VERSION 5.8 ;
BUSBITCHARS "[]" ;
DIVIDERCHAR "/" ;
UNITS
    DATABASE MICRONS 2000 ;
END UNITS

VIA uart_tx_via1_2_960_340_1_3_300_300
  VIARULE Via1Array-0 ;
  CUTSIZE 0.07 0.07 ;
  LAYERS metal1 via1 metal2 ;
  CUTSPACING 0.08 0.08 ;
  ENCLOSURE 0.035 0.05 0.035 0.035 ;
  ROWCOL 1 3 ;
END uart_tx_via1_2_960_340_1_3_300_300

VIA uart_tx_via2_3_960_340_1_3_320_320
  VIARULE Via2Array-0 ;
  CUTSIZE 0.07 0.07 ;
  LAYERS metal2 via2 metal3 ;
  CUTSPACING 0.09 0.09 ;
  ENCLOSURE 0.035 0.035 0.035 0.035 ;
  ROWCOL 1 3 ;
END uart_tx_via2_3_960_340_1_3_320_320

VIA uart_tx_via3_4_960_340_1_3_320_320
  VIARULE Via3Array-0 ;
  CUTSIZE 0.07 0.07 ;
  LAYERS metal3 via3 metal4 ;
  CUTSPACING 0.09 0.09 ;
  ENCLOSURE 0.035 0.035 0.045 0.035 ;
  ROWCOL 1 3 ;
END uart_tx_via3_4_960_340_1_3_320_320

VIA uart_tx_via4_5_960_2800_5_2_600_600
  VIARULE Via4Array-0 ;
  CUTSIZE 0.14 0.14 ;
  LAYERS metal4 via4 metal5 ;
  CUTSPACING 0.16 0.16 ;
  ENCLOSURE 0.02 0 0 0 ;
  ROWCOL 5 2 ;
END uart_tx_via4_5_960_2800_5_2_600_600

VIA uart_tx_via5_6_960_2800_5_2_600_600
  VIARULE Via5Array-0 ;
  CUTSIZE 0.14 0.14 ;
  LAYERS metal5 via5 metal6 ;
  CUTSPACING 0.16 0.16 ;
  ENCLOSURE 0 0 0 0 ;
  ROWCOL 5 2 ;
END uart_tx_via5_6_960_2800_5_2_600_600

VIA uart_tx_via6_7_960_2800_4_1_600_600
  VIARULE Via6Array-0 ;
  CUTSIZE 0.14 0.14 ;
  LAYERS metal6 via6 metal7 ;
  CUTSPACING 0.16 0.16 ;
  ENCLOSURE 0 0 0.13 0.18 ;
  ROWCOL 4 1 ;
END uart_tx_via6_7_960_2800_4_1_600_600

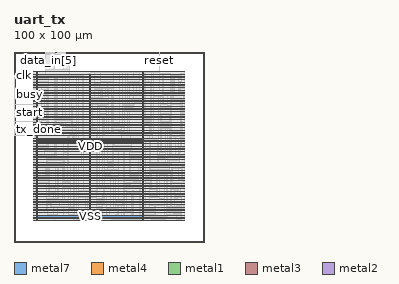
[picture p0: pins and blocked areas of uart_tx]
MACRO uart_tx
  FOREIGN uart_tx 0 0 ;
  CLASS BLOCK ;
  SIZE 100 BY 100 ;
  PIN VSS
    USE GROUND ;
    DIRECTION INOUT ;
    PORT
      LAYER metal7 ;
        RECT  11.83 52.5 68.31 53.9 ;
        RECT  11.83 12.5 68.31 13.9 ;
      LAYER metal4 ;
        RECT  67.83 11.115 68.31 89.685 ;
        RECT  11.83 11.115 12.31 89.685 ;
      LAYER metal1 ;
        RECT  10.07 89.515 89.87 89.685 ;
        RECT  10.07 86.715 89.87 86.885 ;
        RECT  10.07 83.915 89.87 84.085 ;
        RECT  10.07 81.115 89.87 81.285 ;
        RECT  10.07 78.315 89.87 78.485 ;
        RECT  10.07 75.515 89.87 75.685 ;
        RECT  10.07 72.715 89.87 72.885 ;
        RECT  10.07 69.915 89.87 70.085 ;
        RECT  10.07 67.115 89.87 67.285 ;
        RECT  10.07 64.315 89.87 64.485 ;
        RECT  10.07 61.515 89.87 61.685 ;
        RECT  10.07 58.715 89.87 58.885 ;
        RECT  10.07 55.915 89.87 56.085 ;
        RECT  10.07 53.115 89.87 53.285 ;
        RECT  10.07 50.315 89.87 50.485 ;
        RECT  10.07 47.515 89.87 47.685 ;
        RECT  10.07 44.715 89.87 44.885 ;
        RECT  10.07 41.915 89.87 42.085 ;
        RECT  10.07 39.115 89.87 39.285 ;
        RECT  10.07 36.315 89.87 36.485 ;
        RECT  10.07 33.515 89.87 33.685 ;
        RECT  10.07 30.715 89.87 30.885 ;
        RECT  10.07 27.915 89.87 28.085 ;
        RECT  10.07 25.115 89.87 25.285 ;
        RECT  10.07 22.315 89.87 22.485 ;
        RECT  10.07 19.515 89.87 19.685 ;
        RECT  10.07 16.715 89.87 16.885 ;
        RECT  10.07 13.915 89.87 14.085 ;
        RECT  10.07 11.115 89.87 11.285 ;
      VIA 68.07 53.2 uart_tx_via6_7_960_2800_4_1_600_600 ;
      VIA 68.07 53.2 uart_tx_via5_6_960_2800_5_2_600_600 ;
      VIA 68.07 53.2 uart_tx_via4_5_960_2800_5_2_600_600 ;
      VIA 68.07 13.2 uart_tx_via6_7_960_2800_4_1_600_600 ;
      VIA 68.07 13.2 uart_tx_via5_6_960_2800_5_2_600_600 ;
      VIA 68.07 13.2 uart_tx_via4_5_960_2800_5_2_600_600 ;
      VIA 12.07 53.2 uart_tx_via6_7_960_2800_4_1_600_600 ;
      VIA 12.07 53.2 uart_tx_via5_6_960_2800_5_2_600_600 ;
      VIA 12.07 53.2 uart_tx_via4_5_960_2800_5_2_600_600 ;
      VIA 12.07 13.2 uart_tx_via6_7_960_2800_4_1_600_600 ;
      VIA 12.07 13.2 uart_tx_via5_6_960_2800_5_2_600_600 ;
      VIA 12.07 13.2 uart_tx_via4_5_960_2800_5_2_600_600 ;
      VIA 68.07 89.6 uart_tx_via3_4_960_340_1_3_320_320 ;
      VIA 68.07 89.6 uart_tx_via2_3_960_340_1_3_320_320 ;
      VIA 68.07 89.6 uart_tx_via1_2_960_340_1_3_300_300 ;
      VIA 68.07 86.8 uart_tx_via3_4_960_340_1_3_320_320 ;
      VIA 68.07 86.8 uart_tx_via2_3_960_340_1_3_320_320 ;
      VIA 68.07 86.8 uart_tx_via1_2_960_340_1_3_300_300 ;
      VIA 68.07 84 uart_tx_via3_4_960_340_1_3_320_320 ;
      VIA 68.07 84 uart_tx_via2_3_960_340_1_3_320_320 ;
      VIA 68.07 84 uart_tx_via1_2_960_340_1_3_300_300 ;
      VIA 68.07 81.2 uart_tx_via3_4_960_340_1_3_320_320 ;
      VIA 68.07 81.2 uart_tx_via2_3_960_340_1_3_320_320 ;
      VIA 68.07 81.2 uart_tx_via1_2_960_340_1_3_300_300 ;
      VIA 68.07 78.4 uart_tx_via3_4_960_340_1_3_320_320 ;
      VIA 68.07 78.4 uart_tx_via2_3_960_340_1_3_320_320 ;
      VIA 68.07 78.4 uart_tx_via1_2_960_340_1_3_300_300 ;
      VIA 68.07 75.6 uart_tx_via3_4_960_340_1_3_320_320 ;
      VIA 68.07 75.6 uart_tx_via2_3_960_340_1_3_320_320 ;
      VIA 68.07 75.6 uart_tx_via1_2_960_340_1_3_300_300 ;
      VIA 68.07 72.8 uart_tx_via3_4_960_340_1_3_320_320 ;
      VIA 68.07 72.8 uart_tx_via2_3_960_340_1_3_320_320 ;
      VIA 68.07 72.8 uart_tx_via1_2_960_340_1_3_300_300 ;
      VIA 68.07 70 uart_tx_via3_4_960_340_1_3_320_320 ;
      VIA 68.07 70 uart_tx_via2_3_960_340_1_3_320_320 ;
      VIA 68.07 70 uart_tx_via1_2_960_340_1_3_300_300 ;
      VIA 68.07 67.2 uart_tx_via3_4_960_340_1_3_320_320 ;
      VIA 68.07 67.2 uart_tx_via2_3_960_340_1_3_320_320 ;
      VIA 68.07 67.2 uart_tx_via1_2_960_340_1_3_300_300 ;
      VIA 68.07 64.4 uart_tx_via3_4_960_340_1_3_320_320 ;
      VIA 68.07 64.4 uart_tx_via2_3_960_340_1_3_320_320 ;
      VIA 68.07 64.4 uart_tx_via1_2_960_340_1_3_300_300 ;
      VIA 68.07 61.6 uart_tx_via3_4_960_340_1_3_320_320 ;
      VIA 68.07 61.6 uart_tx_via2_3_960_340_1_3_320_320 ;
      VIA 68.07 61.6 uart_tx_via1_2_960_340_1_3_300_300 ;
      VIA 68.07 58.8 uart_tx_via3_4_960_340_1_3_320_320 ;
      VIA 68.07 58.8 uart_tx_via2_3_960_340_1_3_320_320 ;
      VIA 68.07 58.8 uart_tx_via1_2_960_340_1_3_300_300 ;
      VIA 68.07 56 uart_tx_via3_4_960_340_1_3_320_320 ;
      VIA 68.07 56 uart_tx_via2_3_960_340_1_3_320_320 ;
      VIA 68.07 56 uart_tx_via1_2_960_340_1_3_300_300 ;
      VIA 68.07 53.2 uart_tx_via3_4_960_340_1_3_320_320 ;
      VIA 68.07 53.2 uart_tx_via2_3_960_340_1_3_320_320 ;
      VIA 68.07 53.2 uart_tx_via1_2_960_340_1_3_300_300 ;
      VIA 68.07 50.4 uart_tx_via3_4_960_340_1_3_320_320 ;
      VIA 68.07 50.4 uart_tx_via2_3_960_340_1_3_320_320 ;
      VIA 68.07 50.4 uart_tx_via1_2_960_340_1_3_300_300 ;
      VIA 68.07 47.6 uart_tx_via3_4_960_340_1_3_320_320 ;
      VIA 68.07 47.6 uart_tx_via2_3_960_340_1_3_320_320 ;
      VIA 68.07 47.6 uart_tx_via1_2_960_340_1_3_300_300 ;
      VIA 68.07 44.8 uart_tx_via3_4_960_340_1_3_320_320 ;
      VIA 68.07 44.8 uart_tx_via2_3_960_340_1_3_320_320 ;
      VIA 68.07 44.8 uart_tx_via1_2_960_340_1_3_300_300 ;
      VIA 68.07 42 uart_tx_via3_4_960_340_1_3_320_320 ;
      VIA 68.07 42 uart_tx_via2_3_960_340_1_3_320_320 ;
      VIA 68.07 42 uart_tx_via1_2_960_340_1_3_300_300 ;
      VIA 68.07 39.2 uart_tx_via3_4_960_340_1_3_320_320 ;
      VIA 68.07 39.2 uart_tx_via2_3_960_340_1_3_320_320 ;
      VIA 68.07 39.2 uart_tx_via1_2_960_340_1_3_300_300 ;
      VIA 68.07 36.4 uart_tx_via3_4_960_340_1_3_320_320 ;
      VIA 68.07 36.4 uart_tx_via2_3_960_340_1_3_320_320 ;
      VIA 68.07 36.4 uart_tx_via1_2_960_340_1_3_300_300 ;
      VIA 68.07 33.6 uart_tx_via3_4_960_340_1_3_320_320 ;
      VIA 68.07 33.6 uart_tx_via2_3_960_340_1_3_320_320 ;
      VIA 68.07 33.6 uart_tx_via1_2_960_340_1_3_300_300 ;
      VIA 68.07 30.8 uart_tx_via3_4_960_340_1_3_320_320 ;
      VIA 68.07 30.8 uart_tx_via2_3_960_340_1_3_320_320 ;
      VIA 68.07 30.8 uart_tx_via1_2_960_340_1_3_300_300 ;
      VIA 68.07 28 uart_tx_via3_4_960_340_1_3_320_320 ;
      VIA 68.07 28 uart_tx_via2_3_960_340_1_3_320_320 ;
      VIA 68.07 28 uart_tx_via1_2_960_340_1_3_300_300 ;
      VIA 68.07 25.2 uart_tx_via3_4_960_340_1_3_320_320 ;
      VIA 68.07 25.2 uart_tx_via2_3_960_340_1_3_320_320 ;
      VIA 68.07 25.2 uart_tx_via1_2_960_340_1_3_300_300 ;
      VIA 68.07 22.4 uart_tx_via3_4_960_340_1_3_320_320 ;
      VIA 68.07 22.4 uart_tx_via2_3_960_340_1_3_320_320 ;
      VIA 68.07 22.4 uart_tx_via1_2_960_340_1_3_300_300 ;
      VIA 68.07 19.6 uart_tx_via3_4_960_340_1_3_320_320 ;
      VIA 68.07 19.6 uart_tx_via2_3_960_340_1_3_320_320 ;
      VIA 68.07 19.6 uart_tx_via1_2_960_340_1_3_300_300 ;
      VIA 68.07 16.8 uart_tx_via3_4_960_340_1_3_320_320 ;
      VIA 68.07 16.8 uart_tx_via2_3_960_340_1_3_320_320 ;
      VIA 68.07 16.8 uart_tx_via1_2_960_340_1_3_300_300 ;
      VIA 68.07 14 uart_tx_via3_4_960_340_1_3_320_320 ;
      VIA 68.07 14 uart_tx_via2_3_960_340_1_3_320_320 ;
      VIA 68.07 14 uart_tx_via1_2_960_340_1_3_300_300 ;
      VIA 68.07 11.2 uart_tx_via3_4_960_340_1_3_320_320 ;
      VIA 68.07 11.2 uart_tx_via2_3_960_340_1_3_320_320 ;
      VIA 68.07 11.2 uart_tx_via1_2_960_340_1_3_300_300 ;
      VIA 12.07 89.6 uart_tx_via3_4_960_340_1_3_320_320 ;
      VIA 12.07 89.6 uart_tx_via2_3_960_340_1_3_320_320 ;
      VIA 12.07 89.6 uart_tx_via1_2_960_340_1_3_300_300 ;
      VIA 12.07 86.8 uart_tx_via3_4_960_340_1_3_320_320 ;
      VIA 12.07 86.8 uart_tx_via2_3_960_340_1_3_320_320 ;
      VIA 12.07 86.8 uart_tx_via1_2_960_340_1_3_300_300 ;
      VIA 12.07 84 uart_tx_via3_4_960_340_1_3_320_320 ;
      VIA 12.07 84 uart_tx_via2_3_960_340_1_3_320_320 ;
      VIA 12.07 84 uart_tx_via1_2_960_340_1_3_300_300 ;
      VIA 12.07 81.2 uart_tx_via3_4_960_340_1_3_320_320 ;
      VIA 12.07 81.2 uart_tx_via2_3_960_340_1_3_320_320 ;
      VIA 12.07 81.2 uart_tx_via1_2_960_340_1_3_300_300 ;
      VIA 12.07 78.4 uart_tx_via3_4_960_340_1_3_320_320 ;
      VIA 12.07 78.4 uart_tx_via2_3_960_340_1_3_320_320 ;
      VIA 12.07 78.4 uart_tx_via1_2_960_340_1_3_300_300 ;
      VIA 12.07 75.6 uart_tx_via3_4_960_340_1_3_320_320 ;
      VIA 12.07 75.6 uart_tx_via2_3_960_340_1_3_320_320 ;
      VIA 12.07 75.6 uart_tx_via1_2_960_340_1_3_300_300 ;
      VIA 12.07 72.8 uart_tx_via3_4_960_340_1_3_320_320 ;
      VIA 12.07 72.8 uart_tx_via2_3_960_340_1_3_320_320 ;
      VIA 12.07 72.8 uart_tx_via1_2_960_340_1_3_300_300 ;
      VIA 12.07 70 uart_tx_via3_4_960_340_1_3_320_320 ;
      VIA 12.07 70 uart_tx_via2_3_960_340_1_3_320_320 ;
      VIA 12.07 70 uart_tx_via1_2_960_340_1_3_300_300 ;
      VIA 12.07 67.2 uart_tx_via3_4_960_340_1_3_320_320 ;
      VIA 12.07 67.2 uart_tx_via2_3_960_340_1_3_320_320 ;
      VIA 12.07 67.2 uart_tx_via1_2_960_340_1_3_300_300 ;
      VIA 12.07 64.4 uart_tx_via3_4_960_340_1_3_320_320 ;
      VIA 12.07 64.4 uart_tx_via2_3_960_340_1_3_320_320 ;
      VIA 12.07 64.4 uart_tx_via1_2_960_340_1_3_300_300 ;
      VIA 12.07 61.6 uart_tx_via3_4_960_340_1_3_320_320 ;
      VIA 12.07 61.6 uart_tx_via2_3_960_340_1_3_320_320 ;
      VIA 12.07 61.6 uart_tx_via1_2_960_340_1_3_300_300 ;
      VIA 12.07 58.8 uart_tx_via3_4_960_340_1_3_320_320 ;
      VIA 12.07 58.8 uart_tx_via2_3_960_340_1_3_320_320 ;
      VIA 12.07 58.8 uart_tx_via1_2_960_340_1_3_300_300 ;
      VIA 12.07 56 uart_tx_via3_4_960_340_1_3_320_320 ;
      VIA 12.07 56 uart_tx_via2_3_960_340_1_3_320_320 ;
      VIA 12.07 56 uart_tx_via1_2_960_340_1_3_300_300 ;
      VIA 12.07 53.2 uart_tx_via3_4_960_340_1_3_320_320 ;
      VIA 12.07 53.2 uart_tx_via2_3_960_340_1_3_320_320 ;
      VIA 12.07 53.2 uart_tx_via1_2_960_340_1_3_300_300 ;
      VIA 12.07 50.4 uart_tx_via3_4_960_340_1_3_320_320 ;
      VIA 12.07 50.4 uart_tx_via2_3_960_340_1_3_320_320 ;
      VIA 12.07 50.4 uart_tx_via1_2_960_340_1_3_300_300 ;
      VIA 12.07 47.6 uart_tx_via3_4_960_340_1_3_320_320 ;
      VIA 12.07 47.6 uart_tx_via2_3_960_340_1_3_320_320 ;
      VIA 12.07 47.6 uart_tx_via1_2_960_340_1_3_300_300 ;
      VIA 12.07 44.8 uart_tx_via3_4_960_340_1_3_320_320 ;
      VIA 12.07 44.8 uart_tx_via2_3_960_340_1_3_320_320 ;
      VIA 12.07 44.8 uart_tx_via1_2_960_340_1_3_300_300 ;
      VIA 12.07 42 uart_tx_via3_4_960_340_1_3_320_320 ;
      VIA 12.07 42 uart_tx_via2_3_960_340_1_3_320_320 ;
      VIA 12.07 42 uart_tx_via1_2_960_340_1_3_300_300 ;
      VIA 12.07 39.2 uart_tx_via3_4_960_340_1_3_320_320 ;
      VIA 12.07 39.2 uart_tx_via2_3_960_340_1_3_320_320 ;
      VIA 12.07 39.2 uart_tx_via1_2_960_340_1_3_300_300 ;
      VIA 12.07 36.4 uart_tx_via3_4_960_340_1_3_320_320 ;
      VIA 12.07 36.4 uart_tx_via2_3_960_340_1_3_320_320 ;
      VIA 12.07 36.4 uart_tx_via1_2_960_340_1_3_300_300 ;
      VIA 12.07 33.6 uart_tx_via3_4_960_340_1_3_320_320 ;
      VIA 12.07 33.6 uart_tx_via2_3_960_340_1_3_320_320 ;
      VIA 12.07 33.6 uart_tx_via1_2_960_340_1_3_300_300 ;
      VIA 12.07 30.8 uart_tx_via3_4_960_340_1_3_320_320 ;
      VIA 12.07 30.8 uart_tx_via2_3_960_340_1_3_320_320 ;
      VIA 12.07 30.8 uart_tx_via1_2_960_340_1_3_300_300 ;
      VIA 12.07 28 uart_tx_via3_4_960_340_1_3_320_320 ;
      VIA 12.07 28 uart_tx_via2_3_960_340_1_3_320_320 ;
      VIA 12.07 28 uart_tx_via1_2_960_340_1_3_300_300 ;
      VIA 12.07 25.2 uart_tx_via3_4_960_340_1_3_320_320 ;
      VIA 12.07 25.2 uart_tx_via2_3_960_340_1_3_320_320 ;
      VIA 12.07 25.2 uart_tx_via1_2_960_340_1_3_300_300 ;
      VIA 12.07 22.4 uart_tx_via3_4_960_340_1_3_320_320 ;
      VIA 12.07 22.4 uart_tx_via2_3_960_340_1_3_320_320 ;
      VIA 12.07 22.4 uart_tx_via1_2_960_340_1_3_300_300 ;
      VIA 12.07 19.6 uart_tx_via3_4_960_340_1_3_320_320 ;
      VIA 12.07 19.6 uart_tx_via2_3_960_340_1_3_320_320 ;
      VIA 12.07 19.6 uart_tx_via1_2_960_340_1_3_300_300 ;
      VIA 12.07 16.8 uart_tx_via3_4_960_340_1_3_320_320 ;
      VIA 12.07 16.8 uart_tx_via2_3_960_340_1_3_320_320 ;
      VIA 12.07 16.8 uart_tx_via1_2_960_340_1_3_300_300 ;
      VIA 12.07 14 uart_tx_via3_4_960_340_1_3_320_320 ;
      VIA 12.07 14 uart_tx_via2_3_960_340_1_3_320_320 ;
      VIA 12.07 14 uart_tx_via1_2_960_340_1_3_300_300 ;
      VIA 12.07 11.2 uart_tx_via3_4_960_340_1_3_320_320 ;
      VIA 12.07 11.2 uart_tx_via2_3_960_340_1_3_320_320 ;
      VIA 12.07 11.2 uart_tx_via1_2_960_340_1_3_300_300 ;
    END
  END VSS
  PIN VDD
    USE POWER ;
    DIRECTION INOUT ;
    PORT
      LAYER metal4 ;
        RECT  39.83 12.515 40.31 88.285 ;
      LAYER metal1 ;
        RECT  10.07 88.115 89.87 88.285 ;
        RECT  10.07 85.315 89.87 85.485 ;
        RECT  10.07 82.515 89.87 82.685 ;
        RECT  10.07 79.715 89.87 79.885 ;
        RECT  10.07 76.915 89.87 77.085 ;
        RECT  10.07 74.115 89.87 74.285 ;
        RECT  10.07 71.315 89.87 71.485 ;
        RECT  10.07 68.515 89.87 68.685 ;
        RECT  10.07 65.715 89.87 65.885 ;
        RECT  10.07 62.915 89.87 63.085 ;
        RECT  10.07 60.115 89.87 60.285 ;
        RECT  10.07 57.315 89.87 57.485 ;
        RECT  10.07 54.515 89.87 54.685 ;
        RECT  10.07 51.715 89.87 51.885 ;
        RECT  10.07 48.915 89.87 49.085 ;
        RECT  10.07 46.115 89.87 46.285 ;
        RECT  10.07 43.315 89.87 43.485 ;
        RECT  10.07 40.515 89.87 40.685 ;
        RECT  10.07 37.715 89.87 37.885 ;
        RECT  10.07 34.915 89.87 35.085 ;
        RECT  10.07 32.115 89.87 32.285 ;
        RECT  10.07 29.315 89.87 29.485 ;
        RECT  10.07 26.515 89.87 26.685 ;
        RECT  10.07 23.715 89.87 23.885 ;
        RECT  10.07 20.915 89.87 21.085 ;
        RECT  10.07 18.115 89.87 18.285 ;
        RECT  10.07 15.315 89.87 15.485 ;
        RECT  10.07 12.515 89.87 12.685 ;
      VIA 40.07 88.2 uart_tx_via3_4_960_340_1_3_320_320 ;
      VIA 40.07 88.2 uart_tx_via2_3_960_340_1_3_320_320 ;
      VIA 40.07 88.2 uart_tx_via1_2_960_340_1_3_300_300 ;
      VIA 40.07 85.4 uart_tx_via3_4_960_340_1_3_320_320 ;
      VIA 40.07 85.4 uart_tx_via2_3_960_340_1_3_320_320 ;
      VIA 40.07 85.4 uart_tx_via1_2_960_340_1_3_300_300 ;
      VIA 40.07 82.6 uart_tx_via3_4_960_340_1_3_320_320 ;
      VIA 40.07 82.6 uart_tx_via2_3_960_340_1_3_320_320 ;
      VIA 40.07 82.6 uart_tx_via1_2_960_340_1_3_300_300 ;
      VIA 40.07 79.8 uart_tx_via3_4_960_340_1_3_320_320 ;
      VIA 40.07 79.8 uart_tx_via2_3_960_340_1_3_320_320 ;
      VIA 40.07 79.8 uart_tx_via1_2_960_340_1_3_300_300 ;
      VIA 40.07 77 uart_tx_via3_4_960_340_1_3_320_320 ;
      VIA 40.07 77 uart_tx_via2_3_960_340_1_3_320_320 ;
      VIA 40.07 77 uart_tx_via1_2_960_340_1_3_300_300 ;
      VIA 40.07 74.2 uart_tx_via3_4_960_340_1_3_320_320 ;
      VIA 40.07 74.2 uart_tx_via2_3_960_340_1_3_320_320 ;
      VIA 40.07 74.2 uart_tx_via1_2_960_340_1_3_300_300 ;
      VIA 40.07 71.4 uart_tx_via3_4_960_340_1_3_320_320 ;
      VIA 40.07 71.4 uart_tx_via2_3_960_340_1_3_320_320 ;
      VIA 40.07 71.4 uart_tx_via1_2_960_340_1_3_300_300 ;
      VIA 40.07 68.6 uart_tx_via3_4_960_340_1_3_320_320 ;
      VIA 40.07 68.6 uart_tx_via2_3_960_340_1_3_320_320 ;
      VIA 40.07 68.6 uart_tx_via1_2_960_340_1_3_300_300 ;
      VIA 40.07 65.8 uart_tx_via3_4_960_340_1_3_320_320 ;
      VIA 40.07 65.8 uart_tx_via2_3_960_340_1_3_320_320 ;
      VIA 40.07 65.8 uart_tx_via1_2_960_340_1_3_300_300 ;
      VIA 40.07 63 uart_tx_via3_4_960_340_1_3_320_320 ;
      VIA 40.07 63 uart_tx_via2_3_960_340_1_3_320_320 ;
      VIA 40.07 63 uart_tx_via1_2_960_340_1_3_300_300 ;
      VIA 40.07 60.2 uart_tx_via3_4_960_340_1_3_320_320 ;
      VIA 40.07 60.2 uart_tx_via2_3_960_340_1_3_320_320 ;
      VIA 40.07 60.2 uart_tx_via1_2_960_340_1_3_300_300 ;
      VIA 40.07 57.4 uart_tx_via3_4_960_340_1_3_320_320 ;
      VIA 40.07 57.4 uart_tx_via2_3_960_340_1_3_320_320 ;
      VIA 40.07 57.4 uart_tx_via1_2_960_340_1_3_300_300 ;
      VIA 40.07 54.6 uart_tx_via3_4_960_340_1_3_320_320 ;
      VIA 40.07 54.6 uart_tx_via2_3_960_340_1_3_320_320 ;
      VIA 40.07 54.6 uart_tx_via1_2_960_340_1_3_300_300 ;
      VIA 40.07 51.8 uart_tx_via3_4_960_340_1_3_320_320 ;
      VIA 40.07 51.8 uart_tx_via2_3_960_340_1_3_320_320 ;
      VIA 40.07 51.8 uart_tx_via1_2_960_340_1_3_300_300 ;
      VIA 40.07 49 uart_tx_via3_4_960_340_1_3_320_320 ;
      VIA 40.07 49 uart_tx_via2_3_960_340_1_3_320_320 ;
      VIA 40.07 49 uart_tx_via1_2_960_340_1_3_300_300 ;
      VIA 40.07 46.2 uart_tx_via3_4_960_340_1_3_320_320 ;
      VIA 40.07 46.2 uart_tx_via2_3_960_340_1_3_320_320 ;
      VIA 40.07 46.2 uart_tx_via1_2_960_340_1_3_300_300 ;
      VIA 40.07 43.4 uart_tx_via3_4_960_340_1_3_320_320 ;
      VIA 40.07 43.4 uart_tx_via2_3_960_340_1_3_320_320 ;
      VIA 40.07 43.4 uart_tx_via1_2_960_340_1_3_300_300 ;
      VIA 40.07 40.6 uart_tx_via3_4_960_340_1_3_320_320 ;
      VIA 40.07 40.6 uart_tx_via2_3_960_340_1_3_320_320 ;
      VIA 40.07 40.6 uart_tx_via1_2_960_340_1_3_300_300 ;
      VIA 40.07 37.8 uart_tx_via3_4_960_340_1_3_320_320 ;
      VIA 40.07 37.8 uart_tx_via2_3_960_340_1_3_320_320 ;
      VIA 40.07 37.8 uart_tx_via1_2_960_340_1_3_300_300 ;
      VIA 40.07 35 uart_tx_via3_4_960_340_1_3_320_320 ;
      VIA 40.07 35 uart_tx_via2_3_960_340_1_3_320_320 ;
      VIA 40.07 35 uart_tx_via1_2_960_340_1_3_300_300 ;
      VIA 40.07 32.2 uart_tx_via3_4_960_340_1_3_320_320 ;
      VIA 40.07 32.2 uart_tx_via2_3_960_340_1_3_320_320 ;
      VIA 40.07 32.2 uart_tx_via1_2_960_340_1_3_300_300 ;
      VIA 40.07 29.4 uart_tx_via3_4_960_340_1_3_320_320 ;
      VIA 40.07 29.4 uart_tx_via2_3_960_340_1_3_320_320 ;
      VIA 40.07 29.4 uart_tx_via1_2_960_340_1_3_300_300 ;
      VIA 40.07 26.6 uart_tx_via3_4_960_340_1_3_320_320 ;
      VIA 40.07 26.6 uart_tx_via2_3_960_340_1_3_320_320 ;
      VIA 40.07 26.6 uart_tx_via1_2_960_340_1_3_300_300 ;
      VIA 40.07 23.8 uart_tx_via3_4_960_340_1_3_320_320 ;
      VIA 40.07 23.8 uart_tx_via2_3_960_340_1_3_320_320 ;
      VIA 40.07 23.8 uart_tx_via1_2_960_340_1_3_300_300 ;
      VIA 40.07 21 uart_tx_via3_4_960_340_1_3_320_320 ;
      VIA 40.07 21 uart_tx_via2_3_960_340_1_3_320_320 ;
      VIA 40.07 21 uart_tx_via1_2_960_340_1_3_300_300 ;
      VIA 40.07 18.2 uart_tx_via3_4_960_340_1_3_320_320 ;
      VIA 40.07 18.2 uart_tx_via2_3_960_340_1_3_320_320 ;
      VIA 40.07 18.2 uart_tx_via1_2_960_340_1_3_300_300 ;
      VIA 40.07 15.4 uart_tx_via3_4_960_340_1_3_320_320 ;
      VIA 40.07 15.4 uart_tx_via2_3_960_340_1_3_320_320 ;
      VIA 40.07 15.4 uart_tx_via1_2_960_340_1_3_300_300 ;
      VIA 40.07 12.6 uart_tx_via3_4_960_340_1_3_320_320 ;
      VIA 40.07 12.6 uart_tx_via2_3_960_340_1_3_320_320 ;
      VIA 40.07 12.6 uart_tx_via1_2_960_340_1_3_300_300 ;
    END
  END VDD
  PIN busy
    DIRECTION OUTPUT ;
    USE SIGNAL ;
    PORT
      LAYER metal3 ;
        RECT  0 77.595 0.07 77.665 ;
    END
  END busy
  PIN clk
    DIRECTION INPUT ;
    USE SIGNAL ;
    PORT
      LAYER metal3 ;
        RECT  0 87.395 0.07 87.465 ;
    END
  END clk
  PIN data_in[0]
    DIRECTION INPUT ;
    USE SIGNAL ;
    PORT
      LAYER metal2 ;
        RECT  20.96 99.93 21.03 100 ;
    END
  END data_in[0]
  PIN data_in[1]
    DIRECTION INPUT ;
    USE SIGNAL ;
    PORT
      LAYER metal2 ;
        RECT  22.48 99.93 22.55 100 ;
    END
  END data_in[1]
  PIN data_in[2]
    DIRECTION INPUT ;
    USE SIGNAL ;
    PORT
      LAYER metal2 ;
        RECT  21.72 99.93 21.79 100 ;
    END
  END data_in[2]
  PIN data_in[3]
    DIRECTION INPUT ;
    USE SIGNAL ;
    PORT
      LAYER metal2 ;
        RECT  22.1 99.93 22.17 100 ;
    END
  END data_in[3]
  PIN data_in[4]
    DIRECTION INPUT ;
    USE SIGNAL ;
    PORT
      LAYER metal2 ;
        RECT  21.34 99.93 21.41 100 ;
    END
  END data_in[4]
  PIN data_in[5]
    DIRECTION INPUT ;
    USE SIGNAL ;
    PORT
      LAYER metal2 ;
        RECT  17.92 99.93 17.99 100 ;
    END
  END data_in[5]
  PIN data_in[6]
    DIRECTION INPUT ;
    USE SIGNAL ;
    PORT
      LAYER metal2 ;
        RECT  16.4 99.93 16.47 100 ;
    END
  END data_in[6]
  PIN data_in[7]
    DIRECTION INPUT ;
    USE SIGNAL ;
    PORT
      LAYER metal2 ;
        RECT  18.3 99.93 18.37 100 ;
    END
  END data_in[7]
  PIN reset
    DIRECTION INPUT ;
    USE SIGNAL ;
    PORT
      LAYER metal2 ;
        RECT  76.44 99.93 76.51 100 ;
    END
  END reset
  PIN start
    DIRECTION INPUT ;
    USE SIGNAL ;
    PORT
      LAYER metal3 ;
        RECT  0 68.075 0.07 68.145 ;
    END
  END start
  PIN tx
    DIRECTION OUTPUT ;
    USE SIGNAL ;
    PORT
      LAYER metal3 ;
        RECT  0 72.835 0.07 72.905 ;
    END
  END tx
  PIN tx_done
    DIRECTION OUTPUT ;
    USE SIGNAL ;
    PORT
      LAYER metal3 ;
        RECT  0 63.595 0.07 63.665 ;
    END
  END tx_done
  OBS
    LAYER metal1 ;
     RECT  10.07 11.115 89.87 89.685 ;
    LAYER metal2 ;
     RECT  57.44 11.795 57.51 11.935 ;
     RECT  31.41 11.795 31.86 12.355 ;
     RECT  67.84 11.13 68.3 12.355 ;
     RECT  72.45 11.935 79.55 12.355 ;
     RECT  31.41 12.355 32.24 12.495 ;
     RECT  37.68 11.935 37.75 12.53 ;
     RECT  21.15 11.935 21.22 12.775 ;
     RECT  31.41 12.495 33 12.915 ;
     RECT  37.68 12.53 40.3 12.915 ;
     RECT  51.74 11.935 57.51 12.915 ;
     RECT  20.77 12.775 21.22 13.055 ;
     RECT  51.74 12.915 58.27 13.055 ;
     RECT  62.19 11.935 63.97 13.055 ;
     RECT  67.84 12.355 79.55 13.195 ;
     RECT  19.82 13.055 25.21 13.265 ;
     RECT  20.58 13.265 25.21 13.335 ;
     RECT  31.41 12.915 40.3 13.335 ;
     RECT  51.74 13.055 63.97 13.335 ;
     RECT  67.84 13.195 80.5 13.335 ;
     RECT  50.03 13.335 80.5 13.405 ;
     RECT  50.03 13.405 50.1 13.475 ;
     RECT  20.58 13.335 26.54 13.685 ;
     RECT  20.77 13.685 26.54 14.035 ;
     RECT  31.41 13.335 42.69 14.035 ;
     RECT  85.37 11.935 88.1 14.215 ;
     RECT  84.99 14.215 88.1 15.155 ;
     RECT  54.4 13.405 80.5 15.855 ;
     RECT  84.61 15.155 88.1 15.855 ;
     RECT  11.84 11.13 12.3 16.555 ;
     RECT  20.77 14.035 42.69 16.555 ;
     RECT  46.61 13.475 50.1 16.555 ;
     RECT  10.7 16.555 12.3 16.625 ;
     RECT  10.89 16.625 12.3 16.975 ;
     RECT  10.89 16.975 12.67 17.115 ;
     RECT  10.89 17.115 14.19 17.465 ;
     RECT  20.77 16.555 50.1 17.535 ;
     RECT  54.4 15.855 88.1 17.535 ;
     RECT  20.77 17.535 88.1 17.745 ;
     RECT  24 17.745 88.1 18.585 ;
     RECT  24 18.585 57.89 18.725 ;
     RECT  11.65 17.465 14.19 18.935 ;
     RECT  18.3 17.955 19.7 18.935 ;
     RECT  61.81 18.585 88.1 18.935 ;
     RECT  61.81 18.935 89.05 19.845 ;
     RECT  62.38 19.845 87.91 20.545 ;
     RECT  11.65 18.935 19.7 21.735 ;
     RECT  24 18.725 57.13 21.735 ;
     RECT  11.08 21.735 57.13 21.945 ;
     RECT  11.27 21.945 57.13 22.715 ;
     RECT  11.27 22.715 58.27 22.785 ;
     RECT  62.76 20.545 87.91 24.045 ;
     RECT  62.76 24.045 87.53 24.535 ;
     RECT  11.65 22.785 58.27 25.235 ;
     RECT  62.19 24.535 87.53 25.235 ;
     RECT  11.65 25.235 87.53 28.455 ;
     RECT  11.27 28.455 88.1 30.555 ;
     RECT  10.89 30.555 88.1 31.255 ;
     RECT  10.89 31.255 89.05 32.865 ;
     RECT  10.89 32.865 88.48 34.055 ;
     RECT  10.7 34.055 88.48 34.405 ;
     RECT  11.46 34.405 50.86 35.665 ;
     RECT  54.97 34.405 88.48 36.785 ;
     RECT  54.97 36.785 83.16 37.065 ;
     RECT  16.4 35.665 50.86 38.255 ;
     RECT  54.97 37.065 81.64 38.255 ;
     RECT  11.46 35.665 12.3 39.515 ;
     RECT  16.4 38.255 81.64 39.515 ;
     RECT  11.46 39.515 81.64 39.655 ;
     RECT  88.41 36.785 88.48 39.795 ;
     RECT  88.41 39.795 89.05 39.865 ;
     RECT  11.27 39.655 81.64 41.055 ;
     RECT  11.27 41.055 82.78 41.545 ;
     RECT  11.46 41.545 82.78 41.755 ;
     RECT  11.46 41.755 87.15 41.825 ;
     RECT  11.46 41.825 86.96 42.665 ;
     RECT  11.46 42.665 28.82 43.785 ;
     RECT  11.46 43.785 28.25 45.045 ;
     RECT  32.93 42.665 86.96 45.745 ;
     RECT  76.82 45.745 86.96 47.215 ;
     RECT  16.21 45.045 28.25 47.635 ;
     RECT  32.93 45.745 72.71 47.635 ;
     RECT  16.21 47.635 72.71 48.405 ;
     RECT  11.46 45.045 12.3 49.455 ;
     RECT  16.21 48.405 61.88 49.455 ;
     RECT  66.18 48.405 72.71 49.735 ;
     RECT  76.82 47.215 87.53 49.735 ;
     RECT  66.18 49.735 88.48 49.945 ;
     RECT  11.46 49.455 61.88 50.645 ;
     RECT  11.84 50.645 61.88 52.255 ;
     RECT  66.18 49.945 88.1 52.255 ;
     RECT  11.84 52.255 88.1 53.445 ;
     RECT  11.84 53.445 56.75 53.725 ;
     RECT  61.43 53.445 88.1 53.795 ;
     RECT  61.43 53.795 89.05 54.145 ;
     RECT  77.01 54.145 89.05 55.265 ;
     RECT  61.43 54.145 72.71 56.385 ;
     RECT  61.43 56.385 72.52 56.525 ;
     RECT  77.01 55.265 88.67 59.255 ;
     RECT  11.84 53.725 56.56 59.395 ;
     RECT  63.71 56.525 72.52 60.655 ;
     RECT  76.44 59.255 88.67 60.655 ;
     RECT  11.46 59.395 56.56 60.795 ;
     RECT  63.71 60.655 88.67 60.795 ;
     RECT  11.46 60.795 88.67 60.865 ;
     RECT  37.11 60.865 88.67 62.475 ;
     RECT  37.11 62.475 88.86 63.245 ;
     RECT  11.46 60.865 33.19 63.875 ;
     RECT  37.11 63.245 88.29 64.085 ;
     RECT  10.89 63.875 33.19 64.855 ;
     RECT  37.11 64.085 87.91 64.855 ;
     RECT  10.89 64.855 87.91 66.885 ;
     RECT  10.89 66.885 55.04 67.445 ;
     RECT  60.1 66.885 87.91 67.865 ;
     RECT  67.51 67.865 87.91 70.595 ;
     RECT  60.1 67.865 63.02 70.735 ;
     RECT  10.89 67.445 51.81 71.365 ;
     RECT  11.65 71.365 51.81 71.855 ;
     RECT  58.01 70.735 63.02 71.855 ;
     RECT  11.65 71.855 63.02 72.135 ;
     RECT  11.65 72.135 63.59 73.115 ;
     RECT  67.51 70.595 88.48 73.115 ;
     RECT  11.65 73.115 88.48 74.655 ;
     RECT  11.65 74.655 89.05 74.865 ;
     RECT  11.65 74.865 58.65 75.145 ;
     RECT  11.65 75.145 24.45 76.755 ;
     RECT  10.7 76.755 24.45 76.965 ;
     RECT  62.76 74.865 89.05 77.945 ;
     RECT  29.13 75.145 58.65 78.645 ;
     RECT  10.89 76.965 24.45 78.995 ;
     RECT  29.13 78.645 54.28 78.995 ;
     RECT  83.09 77.945 89.05 79.065 ;
     RECT  62.76 77.945 78.79 80.535 ;
     RECT  10.89 78.995 54.28 80.745 ;
     RECT  59.34 80.535 78.79 81.795 ;
     RECT  83.09 79.065 87.72 81.795 ;
     RECT  49.08 80.745 54.28 82.635 ;
     RECT  59.34 81.795 87.72 82.635 ;
     RECT  49.08 82.635 87.72 83.755 ;
     RECT  49.08 83.755 88.1 84.245 ;
     RECT  10.89 80.745 45.16 84.595 ;
     RECT  49.08 84.245 72.52 84.595 ;
     RECT  76.63 84.245 88.1 86.135 ;
     RECT  76.63 86.135 88.29 87.185 ;
     RECT  10.89 84.595 72.52 87.325 ;
     RECT  76.63 87.185 88.1 87.325 ;
     RECT  11.27 87.325 40.6 87.465 ;
     RECT  58.96 87.325 72.52 87.605 ;
     RECT  11.84 87.465 40.6 87.745 ;
     RECT  76.63 87.325 87.91 87.745 ;
     RECT  16.4 87.745 40.6 87.885 ;
     RECT  58.96 87.605 59.03 87.885 ;
     RECT  84.23 87.745 87.91 87.885 ;
     RECT  11.84 87.745 12.48 88.025 ;
     RECT  35.97 87.885 40.6 88.305 ;
     RECT  39.39 88.305 40.6 88.445 ;
     RECT  49.27 87.325 54.66 88.445 ;
     RECT  64.09 87.605 70.62 88.445 ;
     RECT  76.63 87.745 77.08 88.445 ;
     RECT  87.84 87.885 87.91 88.445 ;
     RECT  44.9 87.325 45.16 88.585 ;
     RECT  53.26 88.445 53.33 88.865 ;
     RECT  67.84 88.445 70.62 88.865 ;
     RECT  40.15 88.445 40.22 89.005 ;
     RECT  11.84 88.025 12.3 89.67 ;
     RECT  67.84 88.865 68.3 89.67 ;
     RECT  16.4 87.885 29.39 90.965 ;
     RECT  16.4 90.965 21.41 98.455 ;
     RECT  26.28 90.965 29.39 98.525 ;
     RECT  16.4 98.455 21.79 99.015 ;
     RECT  26.28 98.525 27.11 99.015 ;
     RECT  16.4 99.015 27.11 99.085 ;
     RECT  27.04 99.085 27.11 99.785 ;
     RECT  16.4 99.085 22.55 99.965 ;
     RECT  76.44 88.935 76.51 99.965 ;
     RECT  17.16 99.965 17.8 100 ;
    LAYER metal3 ;
     RECT  0 72.555 0.035 72.765 ;
     RECT  0.035 72.555 0.13 72.905 ;
     RECT  0.035 87.395 0.13 87.465 ;
     RECT  0.035 77.595 10.7 77.665 ;
     RECT  10.7 17.535 10.89 22.645 ;
     RECT  0.035 63.595 10.89 63.665 ;
     RECT  0.13 72.555 10.89 72.625 ;
     RECT  10.7 76.895 10.89 77.665 ;
     RECT  10.89 17.395 11.08 22.645 ;
     RECT  10.7 25.795 11.08 25.865 ;
     RECT  11.08 17.395 11.27 25.865 ;
     RECT  10.89 30.555 11.27 30.625 ;
     RECT  10.7 34.335 11.46 35.805 ;
     RECT  10.7 60.375 11.65 60.445 ;
     RECT  10.89 63.595 11.65 64.925 ;
     RECT  11.27 17.395 11.84 30.625 ;
     RECT  11.46 34.335 11.84 36.085 ;
     RECT  10.7 41.335 11.84 45.465 ;
     RECT  10.7 50.575 11.84 50.645 ;
     RECT  10.7 55.195 11.84 55.265 ;
     RECT  11.65 59.955 11.84 64.925 ;
     RECT  0.035 68.075 11.84 68.145 ;
     RECT  10.89 71.295 11.84 72.625 ;
     RECT  10.89 76.895 11.84 77.945 ;
     RECT  11.27 81.795 11.84 81.865 ;
     RECT  11.27 86.555 11.84 86.625 ;
     RECT  11.84 11.13 12.3 89.67 ;
     RECT  12.3 59.395 13.29 64.925 ;
     RECT  12.3 49.595 14 50.645 ;
     RECT  13.29 63.595 14.38 64.925 ;
     RECT  12.3 71.155 14.38 81.865 ;
     RECT  12.3 53.515 15.26 55.545 ;
     RECT  15.26 53.095 15.45 55.545 ;
     RECT  14.38 64.575 15.64 64.925 ;
     RECT  12.3 67.795 15.64 68.145 ;
     RECT  15.64 64.575 15.83 68.145 ;
     RECT  14.38 71.155 15.83 77.525 ;
     RECT  12.3 34.335 16.59 36.085 ;
     RECT  16.59 34.055 16.97 36.085 ;
     RECT  12.3 39.515 16.97 45.605 ;
     RECT  14 49.595 16.97 49.805 ;
     RECT  15.45 53.095 16.97 55.685 ;
     RECT  12.3 16.975 17.04 31.185 ;
     RECT  16.97 48.475 17.35 55.685 ;
     RECT  13.29 59.395 17.35 60.585 ;
     RECT  15.83 64.575 17.35 77.525 ;
     RECT  16.97 34.055 17.42 45.605 ;
     RECT  12.3 86.135 17.42 87.465 ;
     RECT  12.3 13.335 17.54 13.405 ;
     RECT  17.04 16.975 17.54 20.265 ;
     RECT  17.35 48.475 17.73 77.525 ;
     RECT  14.38 80.395 17.73 81.865 ;
     RECT  17.54 13.335 17.8 20.265 ;
     RECT  17.42 34.055 17.8 45.465 ;
     RECT  17.73 48.475 17.92 81.865 ;
     RECT  17.8 34.055 17.99 41.405 ;
     RECT  17.92 48.335 18.11 82.565 ;
     RECT  17.42 86.135 18.11 87.325 ;
     RECT  17.04 23.975 18.3 31.185 ;
     RECT  17.99 34.055 18.3 39.865 ;
     RECT  18.3 23.975 18.94 39.865 ;
     RECT  17.8 17.955 19.32 20.265 ;
     RECT  17.8 13.335 19.82 14.245 ;
     RECT  18.94 23.975 20.77 25.865 ;
     RECT  19.32 17.955 20.96 18.725 ;
     RECT  17.8 44.275 21.15 45.465 ;
     RECT  21.15 44.135 21.34 45.465 ;
     RECT  18.11 48.335 21.34 87.325 ;
     RECT  21.34 44.135 21.62 87.325 ;
     RECT  20.77 22.855 21.91 25.865 ;
     RECT  18.94 28.735 21.91 39.865 ;
     RECT  21.72 98.455 22.1 98.525 ;
     RECT  21.62 44.135 22.17 87.465 ;
     RECT  22.17 44.135 22.48 56.945 ;
     RECT  22.17 60.515 22.55 87.465 ;
     RECT  20.96 90.895 22.55 90.965 ;
     RECT  19.82 13.055 22.67 14.245 ;
     RECT  20.96 17.115 22.67 18.725 ;
     RECT  22.55 65.695 22.74 87.465 ;
     RECT  21.91 22.855 22.86 39.865 ;
     RECT  22.86 21.875 23.62 39.865 ;
     RECT  23.62 21.595 25.59 39.865 ;
     RECT  22.74 65.695 25.71 87.185 ;
     RECT  25.59 31.815 25.9 39.865 ;
     RECT  22.48 43.995 25.9 56.945 ;
     RECT  22.55 60.515 25.9 62.545 ;
     RECT  25.9 31.815 25.97 56.945 ;
     RECT  22.67 13.055 26.1 18.725 ;
     RECT  25.59 21.595 26.54 28.945 ;
     RECT  25.97 31.815 26.54 44.345 ;
     RECT  25.71 65.695 26.85 87.465 ;
     RECT  25.9 60.515 26.92 62.685 ;
     RECT  22.1 98.455 27.11 99.785 ;
     RECT  26.54 31.815 28.06 44.065 ;
     RECT  26.1 12.915 28.75 18.725 ;
     RECT  26.54 21.595 28.75 28.805 ;
     RECT  28.75 12.915 28.82 28.805 ;
     RECT  25.97 47.355 29.01 56.945 ;
     RECT  26.85 65.695 29.39 87.605 ;
     RECT  27.11 98.455 29.39 98.525 ;
     RECT  28.82 18.935 29.7 28.805 ;
     RECT  28.06 31.815 29.7 43.925 ;
     RECT  26.92 60.935 30.27 62.685 ;
     RECT  29.39 65.695 30.27 75.005 ;
     RECT  29.7 18.935 31.41 43.925 ;
     RECT  29.01 47.355 31.41 56.665 ;
     RECT  28.82 12.915 31.79 14.665 ;
     RECT  31.41 18.935 31.79 56.665 ;
     RECT  31.79 12.915 32.74 56.665 ;
     RECT  30.27 60.935 32.74 75.005 ;
     RECT  32.74 12.915 32.81 75.005 ;
     RECT  29.39 78.015 32.81 87.605 ;
     RECT  32.81 12.915 32.93 14.245 ;
     RECT  32.81 17.255 33.12 75.005 ;
     RECT  32.81 78.015 33.12 87.465 ;
     RECT  33.12 17.255 33.76 87.465 ;
     RECT  33.76 17.255 33.95 53.305 ;
     RECT  33.76 56.175 35.97 87.465 ;
     RECT  33.95 27.195 36.73 53.305 ;
     RECT  35.97 56.175 36.73 88.305 ;
     RECT  33.95 17.255 37.49 23.485 ;
     RECT  32.93 11.935 37.75 14.245 ;
     RECT  37.75 12.53 38.82 14.245 ;
     RECT  37.49 17.115 38.82 23.485 ;
     RECT  36.73 27.195 39.54 88.305 ;
     RECT  38.82 12.53 39.84 23.485 ;
     RECT  39.54 27.195 39.84 88.445 ;
     RECT  39.84 12.53 40.15 88.445 ;
     RECT  40.15 12.53 40.3 89.005 ;
     RECT  40.3 59.815 41.29 72.485 ;
     RECT  40.3 76.195 42.12 89.005 ;
     RECT  40.3 13.195 43.26 23.345 ;
     RECT  43.26 20.055 43.38 23.345 ;
     RECT  40.3 27.335 43.38 56.945 ;
     RECT  43.38 20.055 43.64 56.945 ;
     RECT  43.26 13.195 43.76 17.045 ;
     RECT  43.64 25.235 43.76 56.945 ;
     RECT  41.29 59.815 43.76 72.345 ;
     RECT  43.76 25.235 44.21 72.345 ;
     RECT  42.12 76.195 44.71 80.325 ;
     RECT  44.21 28.455 45.16 71.925 ;
     RECT  42.12 83.335 45.35 89.005 ;
     RECT  44.71 76.055 45.66 80.325 ;
     RECT  43.76 13.055 46.11 17.045 ;
     RECT  45.66 76.055 46.3 80.605 ;
     RECT  45.16 28.455 46.49 65.485 ;
     RECT  46.3 76.195 46.49 80.605 ;
     RECT  46.11 13.335 46.8 17.045 ;
     RECT  43.64 20.055 46.8 21.805 ;
     RECT  44.21 25.235 46.8 25.585 ;
     RECT  46.49 56.595 46.87 65.485 ;
     RECT  46.49 28.455 47.63 53.445 ;
     RECT  46.87 56.735 47.63 65.485 ;
     RECT  45.16 68.495 47.94 71.925 ;
     RECT  46.49 76.475 48.32 80.605 ;
     RECT  47.63 57.715 48.51 65.485 ;
     RECT  47.94 68.495 48.51 72.205 ;
     RECT  46.8 13.335 48.58 25.585 ;
     RECT  48.51 57.715 48.7 72.205 ;
     RECT  48.58 13.335 48.96 14.665 ;
     RECT  47.63 37.975 49.15 53.445 ;
     RECT  48.32 76.475 49.27 80.745 ;
     RECT  48.7 57.715 49.65 72.345 ;
     RECT  49.27 76.475 49.65 80.885 ;
     RECT  48.58 17.535 50.79 25.585 ;
     RECT  47.63 28.455 50.79 34.405 ;
     RECT  48.96 13.335 51.17 13.405 ;
     RECT  49.65 57.715 51.36 80.885 ;
     RECT  49.15 42.315 51.62 53.445 ;
     RECT  51.62 51.275 51.74 53.445 ;
     RECT  51.17 11.935 51.81 13.405 ;
     RECT  51.74 51.275 51.93 53.725 ;
     RECT  49.15 37.975 52.12 39.445 ;
     RECT  51.62 42.315 52.12 48.405 ;
     RECT  51.36 57.015 52.21 80.885 ;
     RECT  50.79 17.535 52.31 34.545 ;
     RECT  52.21 62.195 52.5 80.885 ;
     RECT  45.35 84.315 52.5 89.005 ;
     RECT  51.93 51.275 52.57 53.865 ;
     RECT  52.57 51.275 52.95 52.885 ;
     RECT  52.31 17.395 53.33 34.545 ;
     RECT  51.81 13.055 53.45 13.405 ;
     RECT  53.45 13.055 54.4 14.245 ;
     RECT  53.33 17.395 54.4 19.005 ;
     RECT  52.21 57.015 55.04 59.045 ;
     RECT  54.4 13.055 55.16 19.005 ;
     RECT  53.33 21.875 55.16 34.545 ;
     RECT  52.12 37.975 55.16 48.405 ;
     RECT  55.04 57.015 55.42 58.485 ;
     RECT  52.95 52.535 55.73 52.885 ;
     RECT  52.5 62.195 55.73 89.005 ;
     RECT  55.42 57.015 55.92 58.345 ;
     RECT  55.16 12.915 56.68 19.005 ;
     RECT  55.73 52.535 56.68 53.445 ;
     RECT  55.73 61.775 56.94 89.005 ;
     RECT  56.68 12.355 57.44 19.005 ;
     RECT  55.16 21.875 57.44 48.405 ;
     RECT  57.44 12.355 57.82 48.405 ;
     RECT  56.68 52.535 57.82 53.725 ;
     RECT  57.82 11.795 58.08 48.405 ;
     RECT  58.08 30.135 58.27 48.405 ;
     RECT  55.92 56.735 58.39 58.345 ;
     RECT  56.94 61.775 58.39 69.265 ;
     RECT  56.94 72.275 58.65 89.005 ;
     RECT  58.08 16.975 59.03 26.985 ;
     RECT  57.82 52.395 59.15 53.725 ;
     RECT  58.65 72.415 59.79 89.005 ;
     RECT  58.27 30.135 59.98 31.185 ;
     RECT  58.39 56.735 59.98 69.265 ;
     RECT  59.79 72.415 60.55 83.265 ;
     RECT  59.98 56.735 60.74 69.125 ;
     RECT  58.27 34.195 60.93 48.405 ;
     RECT  59.15 52.395 61.05 53.865 ;
     RECT  58.08 11.795 61.24 13.125 ;
     RECT  59.98 30.275 61.5 31.185 ;
     RECT  60.93 34.195 61.5 44.065 ;
     RECT  61.24 11.795 62 13.265 ;
     RECT  59.03 16.975 62 26.145 ;
     RECT  60.93 46.935 62 48.405 ;
     RECT  61.05 52.395 62 54.005 ;
     RECT  62 11.795 62.38 26.145 ;
     RECT  60.55 72.415 62.57 74.025 ;
     RECT  62.38 11.795 63.02 26.845 ;
     RECT  61.5 31.115 63.14 31.185 ;
     RECT  60.55 77.455 63.14 83.265 ;
     RECT  59.79 87.255 63.14 89.005 ;
     RECT  62.57 72.135 63.4 74.025 ;
     RECT  63.14 31.115 63.78 31.745 ;
     RECT  63.4 73.255 64.35 74.025 ;
     RECT  63.14 77.455 64.66 83.405 ;
     RECT  64.35 73.255 64.73 73.885 ;
     RECT  63.78 31.675 65.42 31.745 ;
     RECT  61.5 35.595 65.42 44.065 ;
     RECT  64.66 77.455 65.8 83.545 ;
     RECT  63.14 86.975 65.8 89.005 ;
     RECT  63.02 11.935 65.99 26.145 ;
     RECT  65.99 11.935 66.18 27.545 ;
     RECT  66.18 11.935 66.75 27.685 ;
     RECT  65.42 31.675 66.75 44.065 ;
     RECT  64.73 73.255 67.51 73.745 ;
     RECT  66.75 11.935 67.7 44.065 ;
     RECT  62 46.935 67.7 54.005 ;
     RECT  60.74 56.875 67.7 69.125 ;
     RECT  67.51 72.135 67.7 73.745 ;
     RECT  67.7 11.935 67.84 54.005 ;
     RECT  67.7 56.875 67.84 73.745 ;
     RECT  65.8 77.455 67.84 89.005 ;
     RECT  67.84 11.13 68.3 89.67 ;
     RECT  68.3 57.715 68.91 89.005 ;
     RECT  68.3 17.395 69.1 54.005 ;
     RECT  68.91 65.555 69.29 89.005 ;
     RECT  69.1 34.335 71.12 54.005 ;
     RECT  68.91 57.715 71.12 62.405 ;
     RECT  69.1 17.395 71.19 31.465 ;
     RECT  71.19 17.395 71.38 20.265 ;
     RECT  71.12 34.335 71.38 62.405 ;
     RECT  71.19 23.415 71.57 31.465 ;
     RECT  71.38 56.735 71.76 62.405 ;
     RECT  71.76 56.875 71.88 62.405 ;
     RECT  69.29 65.555 71.88 83.685 ;
     RECT  71.38 34.335 71.95 53.025 ;
     RECT  71.57 27.475 72.07 31.465 ;
     RECT  71.95 34.335 72.07 38.045 ;
     RECT  71.57 23.415 72.14 24.605 ;
     RECT  72.07 27.475 72.33 38.045 ;
     RECT  71.88 56.875 72.45 83.685 ;
     RECT  69.29 86.555 72.45 89.005 ;
     RECT  72.45 56.875 73.47 89.005 ;
     RECT  68.3 13.335 73.97 14.245 ;
     RECT  73.97 13.195 74.16 14.245 ;
     RECT  71.38 17.395 74.16 19.425 ;
     RECT  74.16 13.195 74.61 19.425 ;
     RECT  72.14 23.415 74.73 23.625 ;
     RECT  74.73 23.275 75.11 23.625 ;
     RECT  72.33 27.475 75.11 37.065 ;
     RECT  75.11 23.275 75.37 37.065 ;
     RECT  71.95 41.055 75.75 53.025 ;
     RECT  75.75 41.055 75.94 44.625 ;
     RECT  73.47 56.875 76.06 76.405 ;
     RECT  75.75 47.775 76.25 53.025 ;
     RECT  76.06 56.595 76.25 76.405 ;
     RECT  75.37 23.275 76.51 35.805 ;
     RECT  73.47 79.975 76.51 89.005 ;
     RECT  76.51 23.275 76.82 35.665 ;
     RECT  76.25 47.775 77.08 76.405 ;
     RECT  77.08 47.775 77.27 68.985 ;
     RECT  77.27 47.775 77.65 67.865 ;
     RECT  77.08 72.135 78.34 76.405 ;
     RECT  76.51 79.975 78.34 88.445 ;
     RECT  78.34 72.135 78.79 88.445 ;
     RECT  74.61 13.195 79.29 19.005 ;
     RECT  76.82 22.995 79.29 35.665 ;
     RECT  75.94 41.055 79.86 44.205 ;
     RECT  77.65 47.775 79.86 59.605 ;
     RECT  79.29 13.195 80.05 35.665 ;
     RECT  80.05 13.195 80.12 35.805 ;
     RECT  80.12 13.195 80.5 14.665 ;
     RECT  80.5 13.335 80.69 14.665 ;
     RECT  79.86 41.055 80.69 59.605 ;
     RECT  78.79 72.135 80.81 77.665 ;
     RECT  80.12 18.655 81 35.805 ;
     RECT  80.69 46.235 81.76 59.605 ;
     RECT  77.65 63.595 81.76 67.865 ;
     RECT  80.69 41.055 81.83 42.665 ;
     RECT  81.76 46.235 82.14 67.865 ;
     RECT  80.81 71.995 82.14 77.665 ;
     RECT  78.79 81.375 82.4 88.445 ;
     RECT  82.14 46.235 82.52 77.665 ;
     RECT  82.4 81.375 82.52 87.745 ;
     RECT  81 18.655 82.59 37.065 ;
     RECT  82.59 18.795 82.78 37.065 ;
     RECT  81.83 41.055 82.78 41.125 ;
     RECT  82.52 46.235 82.78 87.745 ;
     RECT  82.78 58.135 82.97 87.745 ;
     RECT  82.78 31.395 83.09 37.065 ;
     RECT  82.97 76.055 83.16 87.745 ;
     RECT  83.09 31.395 83.54 38.465 ;
     RECT  80.69 14.595 83.85 14.665 ;
     RECT  83.16 76.195 84.11 87.745 ;
     RECT  84.11 77.455 84.3 87.745 ;
     RECT  83.85 14.595 84.49 15.925 ;
     RECT  82.78 18.795 84.68 27.405 ;
     RECT  82.78 46.235 84.8 55.265 ;
     RECT  84.68 22.855 84.87 23.625 ;
     RECT  84.8 45.675 84.87 55.265 ;
     RECT  84.68 18.795 85.44 19.845 ;
     RECT  84.87 23.135 85.82 23.625 ;
     RECT  85.44 18.795 86.01 19.145 ;
     RECT  84.68 27.055 86.51 27.405 ;
     RECT  83.54 32.375 86.58 38.465 ;
     RECT  84.3 77.455 86.58 87.605 ;
     RECT  86.51 27.055 86.77 28.665 ;
     RECT  84.87 45.675 86.77 54.285 ;
     RECT  86.77 45.675 86.96 46.725 ;
     RECT  86.58 77.455 86.96 81.865 ;
     RECT  86.96 77.735 87.34 81.865 ;
     RECT  82.97 58.135 87.46 72.485 ;
     RECT  86.77 49.595 87.53 54.285 ;
     RECT  85.82 23.275 87.65 23.625 ;
     RECT  84.49 15.855 87.84 15.925 ;
     RECT  86.01 18.795 87.84 19.005 ;
     RECT  87.53 53.795 87.84 54.285 ;
     RECT  87.46 58.135 87.84 74.725 ;
     RECT  86.58 86.135 87.84 87.605 ;
     RECT  87.65 23.275 87.91 24.325 ;
     RECT  86.58 32.795 87.91 38.465 ;
     RECT  87.84 53.795 87.91 74.725 ;
     RECT  87.84 15.855 88.1 19.005 ;
     RECT  87.91 62.475 88.29 74.725 ;
     RECT  87.84 86.135 88.29 88.445 ;
     RECT  87.91 32.795 88.48 36.925 ;
     RECT  87.53 49.595 88.48 49.945 ;
     RECT  88.29 66.535 88.48 74.725 ;
     RECT  88.48 36.855 88.67 36.925 ;
     RECT  88.48 49.595 88.67 49.805 ;
     RECT  87.91 53.795 88.67 58.625 ;
     RECT  88.48 66.535 88.67 70.665 ;
     RECT  88.48 32.795 88.86 33.005 ;
     RECT  88.29 62.475 88.86 62.545 ;
     RECT  88.1 17.395 89.05 19.005 ;
     RECT  87.91 24.255 89.05 24.325 ;
     RECT  86.77 28.595 89.05 28.665 ;
     RECT  88.86 32.795 89.05 32.865 ;
     RECT  86.96 45.675 89.05 45.745 ;
     RECT  88.67 49.595 89.05 49.665 ;
     RECT  88.67 53.795 89.05 56.665 ;
     RECT  88.67 66.535 89.05 69.405 ;
     RECT  88.48 74.655 89.05 74.725 ;
     RECT  87.34 77.735 89.05 77.805 ;
     RECT  87.34 80.955 89.05 81.865 ;
     RECT  88.29 88.375 89.05 88.445 ;
    LAYER metal4 ;
     RECT  47.345 20.02 47.485 28.7 ;
     RECT  28.305 40.88 28.445 41.44 ;
     RECT  30.825 55.58 30.965 55.86 ;
     RECT  52.105 58.1 52.245 76.44 ;
     RECT  39.83 12.515 40.31 88.285 ;
     RECT  11.83 11.115 12.31 89.685 ;
     RECT  67.83 11.115 68.31 89.685 ;
    LAYER metal5 ;
     RECT  11.85 12.53 12.29 13.87 ;
     RECT  11.85 52.53 12.29 53.87 ;
     RECT  30.825 70.84 31.525 70.98 ;
     RECT  67.85 12.53 68.29 13.87 ;
     RECT  67.85 52.53 68.29 53.87 ;
    LAYER metal6 ;
     RECT  11.85 12.53 12.29 13.87 ;
     RECT  67.85 12.53 68.29 13.87 ;
     RECT  35.305 39.76 35.445 40.8 ;
     RECT  28.305 40.8 35.445 40.94 ;
     RECT  28.305 40.94 30.405 41.02 ;
     RECT  11.85 52.53 12.29 53.87 ;
     RECT  67.85 52.53 68.29 53.87 ;
     RECT  30.265 41.02 30.405 54.08 ;
     RECT  30.265 54.08 30.965 54.22 ;
     RECT  30.825 54.22 30.965 70.98 ;
     RECT  0.305 56 0.445 74.03 ;
     RECT  0.025 74.03 0.445 74.17 ;
     RECT  0.025 74.17 0.165 87.5 ;
    LAYER metal7 ;
     RECT  0.175 55.87 11.83 56.27 ;
     RECT  11.83 52.5 28.175 56.27 ;
     RECT  28.175 40.67 28.855 56.27 ;
     RECT  28.855 40.67 35.575 53.9 ;
     RECT  11.83 12.5 68.31 13.9 ;
     RECT  35.575 52.5 68.31 53.9 ;
  END
END uart_tx
END LIBRARY
